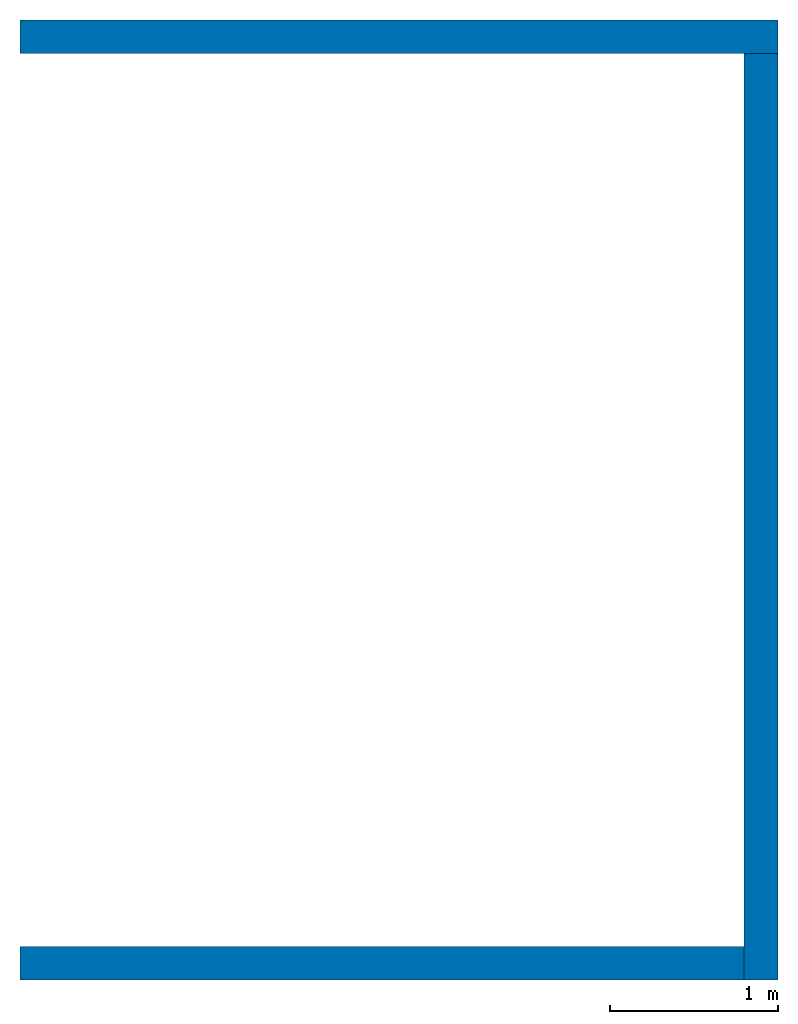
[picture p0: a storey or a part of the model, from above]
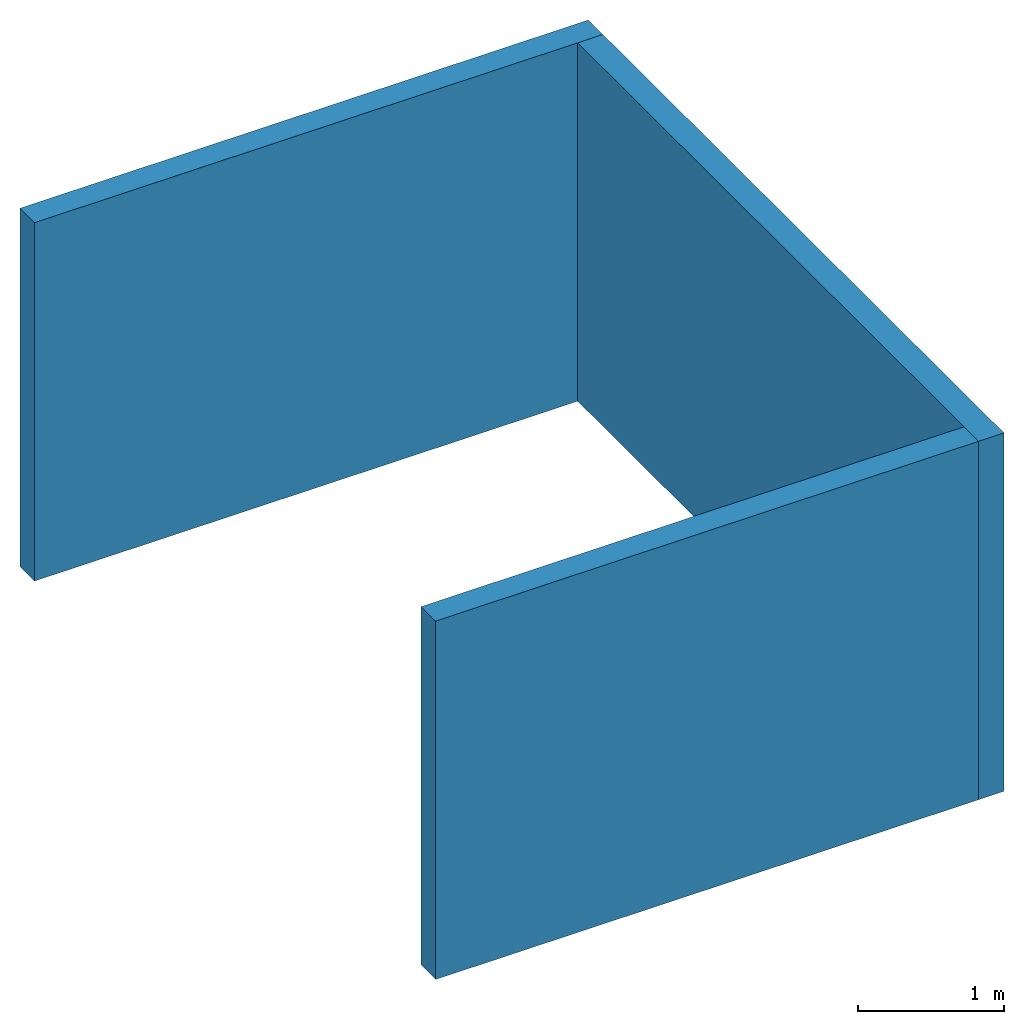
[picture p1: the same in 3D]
Properties of the parts of a building model (IFC2X3)

# File
Description: ViewDefinition [CoordinationView_V2.0, QuantityTakeOffAddOnView]
File name: 0001
Time: 2019-04-04T09:23:02
Written by: The EXPRESS Data Manager Version 5.02.0100.07 : 28 Aug 2013
Made in: 20170223_1515(x64) - Exporter 18.0.0.420 - Alternate UI 18.0.0.420
Comment: STEP Physical File produced by: The EXPRESS Data Manager Version 5.02.0100.07 : 28 Aug 2013 * Module: EDMstepFileFactory/EDMstandAlone * Creation date: Thu Apr 04 09:23:02 2019 * Host: pcvisa16 * Database: C:\Users\vlefort\AppData\Local\Temp\{06775294-77C5-4A6E-96AB-844BA67F9467}\ifc * Database version: 5507 * Database creation date: Thu Apr 04 09:23:00 2019 * Schema: IFC2X3 * Model: DataRepository.ifc * Model creation date: Thu Apr 04 09:23:00 2019 * Header model: DataRepository.ifc_HeaderModel * Header model creation date: Thu Apr 04 09:23:00 2019 * EDMuser: sdai-user * EDMgroup: sdai-group * License ID and type: 5605 : Permanent license. Expiry date: * EDMstepFileFactory options: 020000

# IfcProject, 0001
LongName: Nom du projet; Phase: Etat du projet

# IfcSite, Default
RefLatitude: 48, 51, 23, 999633; RefLongitude: 2, 21, 3, 553905; RefElevation: 0 m
Autre - Adresse du projet: Entrer l'adresse ici; Catégorie: Informations sur le projet; Date de fin du projet: Date de fin; Etat du projet: Etat du projet; Nom du client: Propriétaire; Nom du projet: Nom du projet; Numéro de projet: 0001

# IfcBuilding
Pset_BuildingCommon - NumberOfStoreys: 1
Autre - Catégorie: Informations sur le projet; Adresse du projet: Entrer l'adresse ici; Date de fin du projet: Date de fin; Etat du projet: Etat du projet; Nom du client: Propriétaire; Nom du projet: Nom du projet; Numéro de projet: 0001

# IfcBuildingStorey, Niveau 0
LongName: Niveau 0; Elevation: -1.94916e-14 m
Autre - Catégorie: Niveaux; Famille: Niveau: Ligne du Niveau; Famille et type: Niveau: Ligne du Niveau; ID du type: Niveau: Ligne du Niveau; Type: Niveau: Ligne du Niveau
Contraintes - Elévation: 0 m
Cotes - Hauteur de calcul: 0 m
Données d'identification - Etage de bâtiment: yes; Nom: Niveau 0; Structure: no
Autre(Type) - Catégorie: Niveaux; Nom de la famille: Niveau
Contraintes(Type) - Base de l'élévation: Point de base du projet
Données d'identification(Type) - Nom du type: Ligne du Niveau
Graphismes(Type) - Couleur: 12632256; Epaisseur des lignes: 1; Motif des lignes: Tiret point; Symbole: Marqueur de niveau - Point triangulaire: Marqueur de niveau - Point triangulaire; Valeur par défaut du symbole à l'extrémité 1: no; Valeur par défaut du symbole à l'extrémité 2: yes

# IfcWallStandardCase: Mur de base:Générique - Ext. 200 mm (3)
In: Niveau 0
Type - PredefinedType: STANDARD; Material: Mur par défaut 0.2 m
Type - Autre - Catégorie: Murs; Nom de la famille: Mur de base
Type - Construction - Fonction: Extérieur; Largeur: 0.2 m; Retournement aux extrémités: Aucun(e); Retournement aux insertions: Ne pas retourner
Type - Données d'identification - Nom du type: Générique - Ext. 200 mm
Type - Graphismes - Couleur vue détail faible: 0
Type - Matériaux et finitions - Matériau structurel: Mur par défaut
Type - Propriétés analytiques - Coefficient d'absorbance: 0.7; Rugosité: 3
BaseQuantities - Height: 3 m; Width: 0.2 m
Autre - Famille: Mur de base: Générique - Ext. 200 mm; Famille et type: Mur de base: Générique - Ext. 200 mm; ID du type: Mur de base: Générique - Ext. 200 mm; Type: Mur de base: Générique - Ext. 200 mm
Contraintes - Contrainte inférieure: Niveau: Niveau 0; Contrainte supérieure: Niveau: Niveau 1; Décalage inférieur: 0 m; Décalage supérieur: 0 m; Extension inférieure: 0 m; Extension supérieure: 0 m; Hauteur non contrainte: 3 m; Lié au volume: no; Ligne de justification: Axe du mur; Limite de pièce: yes; Partie inférieure attachée: no; Partie supérieure attachée: no
Structure - Activer le modèle analytique: yes; Enrobage d'armature - Autres faces: Paramètres de l'enrobage d'armature: Enrobage d'armature 1; Enrobage d'armature - Face extérieure: Paramètres de l'enrobage d'armature: Enrobage d'armature 1; Enrobage d'armature - Face intérieure: Paramètres de l'enrobage d'armature: Enrobage d'armature 1; Structure: yes; Utilisation structurelle: Porteur
Pset_WallCommon - Reference: Générique - Ext. 200 mm; LoadBearing: yes; ExtendToStructure: no; IsExternal: yes
Name (Mur de base:Générique - Ext. 200 mm:...) | Length (m) | GrossFootprintArea (m2) | GrossSideArea (m2) = Surface (m2) | GrossVolume (m3) = Volume (m3) | Longueur (m) | Identifiant | Phase de création
247565 | 4.5 | 0.9 | 13.5 | 2.7 | 4.4 | V01 | J1
247616 | 5.5 | 1.1 | 16.5 | 3.3 | 5.5 | V02 | J2
247683 | 4.3 | 0.86 | 12.9 | 2.58 | 4.4 | V03 | J3
